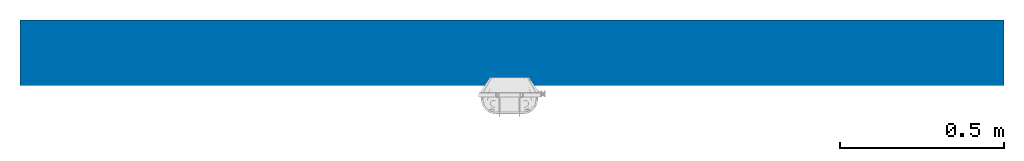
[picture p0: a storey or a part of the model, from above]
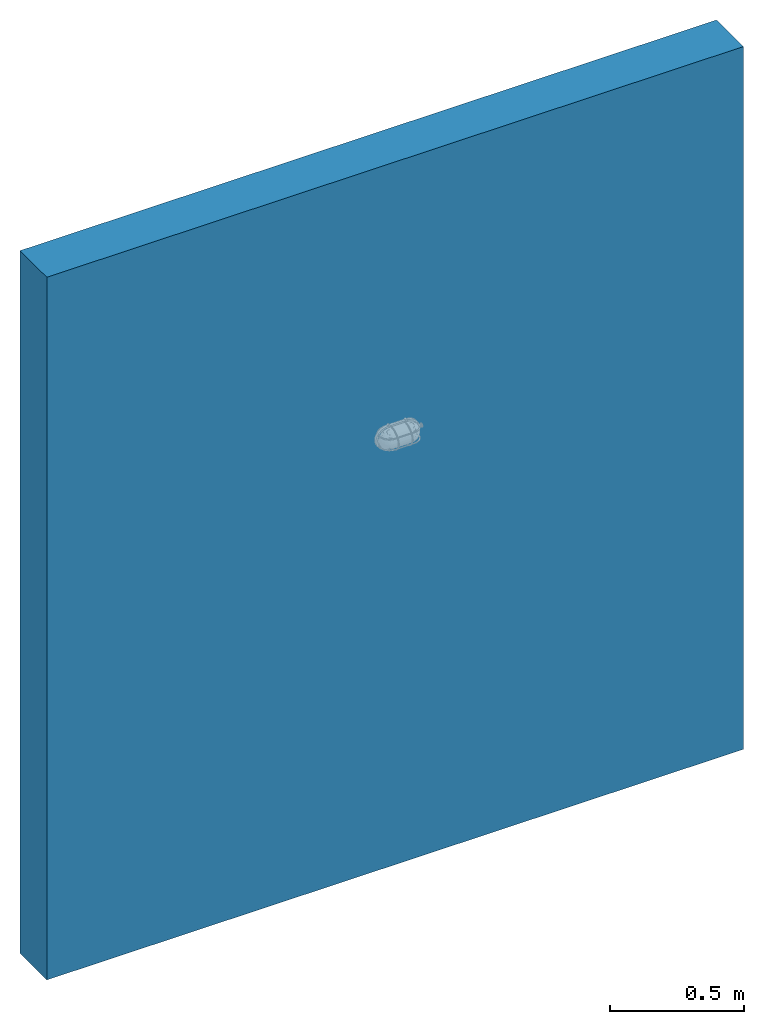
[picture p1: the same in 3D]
Properties of the parts of a building model (IFC2X3)

# File
Description: ViewDefinition [CoordinationView_V2.0], RevitIdentifiers [ContentGUID: cb33d7e8-eb92-4dd9-80de-68bffb1c49f5, VersionGUID: 1d3dac7d-9f9b-464f-9835-0b666bb085d2, NumberOfSaves: 0], CoordinateReference [CoordinateBase: Shared Coordinates]
File name: Project3.ifc
Time: 2026-02-07T23:02:14+03:30
Written by: ODA SDAI 24.12
Made in: Autodesk Revit 25.4.0.32 (ENU) - IFC 25.4.0.32

# IfcProject, Project Number
LongName: home desing; Phase: Project Status

# IfcSite, Default
RefLatitude: 42, 21, 30, 344238; RefLongitude: -71, -3, -35, -194702; RefElevation: 0 m

# IfcBuilding
Pset_BuildingCommon - NumberOfStoreys: 1

# IfcBuildingStorey: Level:8mm Head (5)
Pset_AirSideSystemInformation - sets with these values: 2
Name | LongName = Name | Elevation (m)
Level 1 | Level 1 | 0
Level 2 | Level 2 | 3.2
Level 3 | Level 3 | 6.4
Level 4 | Level 4 | 9.6
Level 5 | Level 5 | 12.8

# IfcBuildingElementProxy: Screw:Screw (4)
In: Level 1
Type - Material: Raw Brass
Pset_BuildingElementProxyCommon - Reference: Screw; sets with these values: 2
Name (Screw:Screw:...)
204447
204448
204449
204450

# IfcDistributionPort, Port_204444_1
Description: Flow; FlowDirection: SOURCEANDSINK

# IfcFlowTerminal: 9 - merchant-bulkhead:Variant 1 - Raw Brass, 9 - merchant-bulkhead:Variant 1 - Raw Brass:204444
In: Level 1
Type - Material: Raw Brass, Mat-Lamp holder, Mat-Glass
Type - Pset_ManufacturerTypeInformation - Manufacturer: Lampfix
Pset_DistributionFlowElementCommon - Reference: Variant 1 - Raw Brass; sets with these values: 2

# IfcOpeningElement: Opening (4)
In: Level 1
Pset_OpeningElementCommon - Reference: Variant 1 - Raw Brass; sets with these values: 2

# IfcWallStandardCase: Basic Wall:Wall 20cm2, Basic Wall:Wall 20cm2:202142
In: Level 1
Type - PredefinedType: STANDARD; Material: Default Wall 0.2 m
Pset_QuantityTakeOff - Reference: Wall 20cm2; sets with these values: 2
Pset_WallCommon - Reference: Wall 20cm2; IsExternal: yes; ExtendToStructure: no; LoadBearing: no
